One B-rep face of a CAD part: STEP entity #73.
In plain terms, the planar face has unit normal (1, 0, 0).
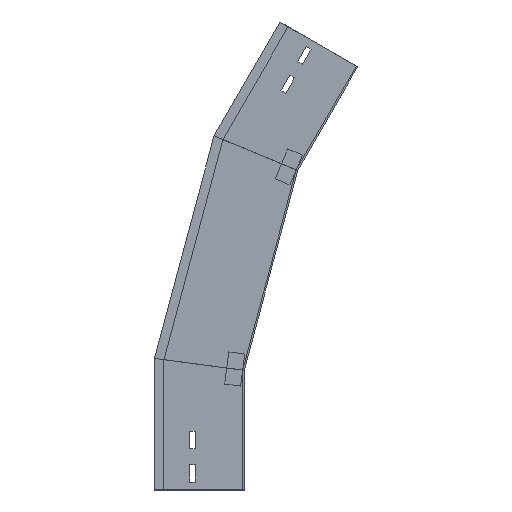
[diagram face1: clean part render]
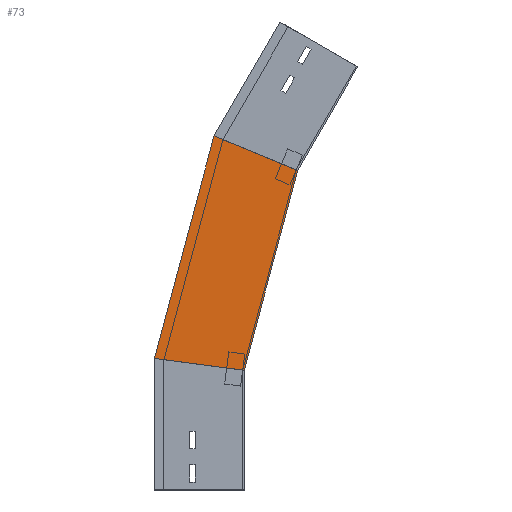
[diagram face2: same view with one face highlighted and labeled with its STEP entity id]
Its self-contained STEP definition (entity closure, numbers rounded to 3 decimals):
#73 = ADVANCED_FACE ( 'NONE', ( #1425 ), #1191, .T. ) ;
#82 = DIRECTION ( 'NONE',  ( 1., 0., 0. ) ) ;
#96 = LINE ( 'NONE', #316, #178 ) ;
#178 = VECTOR ( 'NONE', #649, 1000. ) ;
#202 = CARTESIAN_POINT ( 'NONE',  ( 0., 4.243, 134.167 ) ) ;
#220 = DIRECTION ( 'NONE',  ( 0., -0.991, -0.131 ) ) ;
#244 = EDGE_CURVE ( 'NONE', #568, #1482, #96, .T. ) ;
#300 = CARTESIAN_POINT ( 'NONE',  ( 0., -100.244, 386.419 ) ) ;
#316 = CARTESIAN_POINT ( 'NONE',  ( 0., 112.909, 163.284 ) ) ;
#353 = CARTESIAN_POINT ( 'NONE',  ( 0., -19.411, 147.444 ) ) ;
#482 = CARTESIAN_POINT ( 'NONE',  ( 0., 0., 150. ) ) ;
#540 = DIRECTION ( 'NONE',  ( 0., -0.924, -0.383 ) ) ;
#551 = CARTESIAN_POINT ( 'NONE',  ( 0., 4.243, 134.167 ) ) ;
#568 = VERTEX_POINT ( 'NONE', #684 ) ;
#577 = EDGE_LOOP ( 'NONE', ( #828, #1403, #1145, #1267 ) ) ;
#648 = VECTOR ( 'NONE', #220, 1000. ) ;
#649 = DIRECTION ( 'NONE',  ( 0., -0.259, 0.966 ) ) ;
#684 = CARTESIAN_POINT ( 'NONE',  ( 0., 112.5, 164.811 ) ) ;
#731 = CARTESIAN_POINT ( 'NONE',  ( 0., 37.799, 443.598 ) ) ;
#749 = EDGE_CURVE ( 'NONE', #1056, #1206, #775, .T. ) ;
#775 = LINE ( 'NONE', #202, #1420 ) ;
#828 = ORIENTED_EDGE ( 'NONE', *, *, #244, .T. ) ;
#878 = CARTESIAN_POINT ( 'NONE',  ( 0., -67.034, 400.175 ) ) ;
#891 = AXIS2_PLACEMENT_3D ( 'NONE', #551, #82, #1247 ) ;
#918 = EDGE_CURVE ( 'NONE', #1482, #1206, #1335, .T. ) ;
#1056 = VERTEX_POINT ( 'NONE', #482 ) ;
#1131 = LINE ( 'NONE', #353, #648 ) ;
#1139 = EDGE_CURVE ( 'NONE', #568, #1056, #1131, .T. ) ;
#1145 = ORIENTED_EDGE ( 'NONE', *, *, #749, .F. ) ;
#1191 = PLANE ( 'NONE',  #891 ) ;
#1206 = VERTEX_POINT ( 'NONE', #878 ) ;
#1225 = DIRECTION ( 'NONE',  ( 0., -0.259, 0.966 ) ) ;
#1247 = DIRECTION ( 'NONE',  ( 0., 0., -1. ) ) ;
#1267 = ORIENTED_EDGE ( 'NONE', *, *, #1139, .F. ) ;
#1276 = VECTOR ( 'NONE', #540, 1000. ) ;
#1335 = LINE ( 'NONE', #300, #1276 ) ;
#1403 = ORIENTED_EDGE ( 'NONE', *, *, #918, .T. ) ;
#1420 = VECTOR ( 'NONE', #1225, 1000. ) ;
#1425 = FACE_OUTER_BOUND ( 'NONE', #577, .T. ) ;
#1482 = VERTEX_POINT ( 'NONE', #731 ) ;
